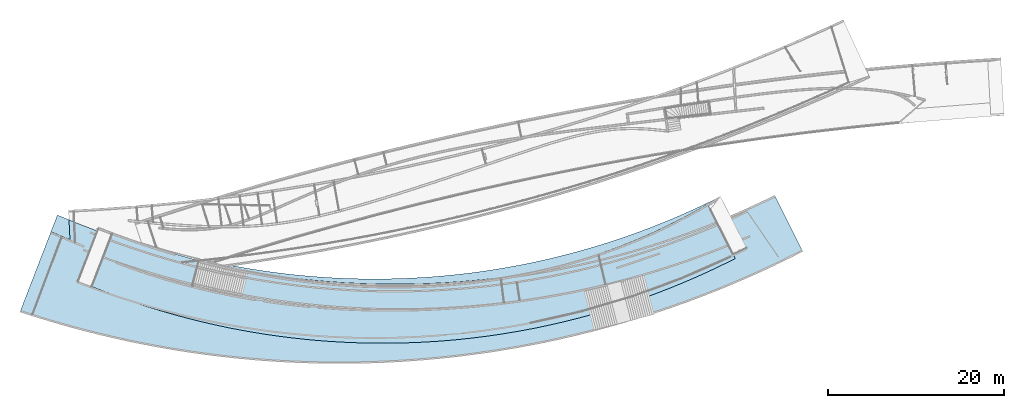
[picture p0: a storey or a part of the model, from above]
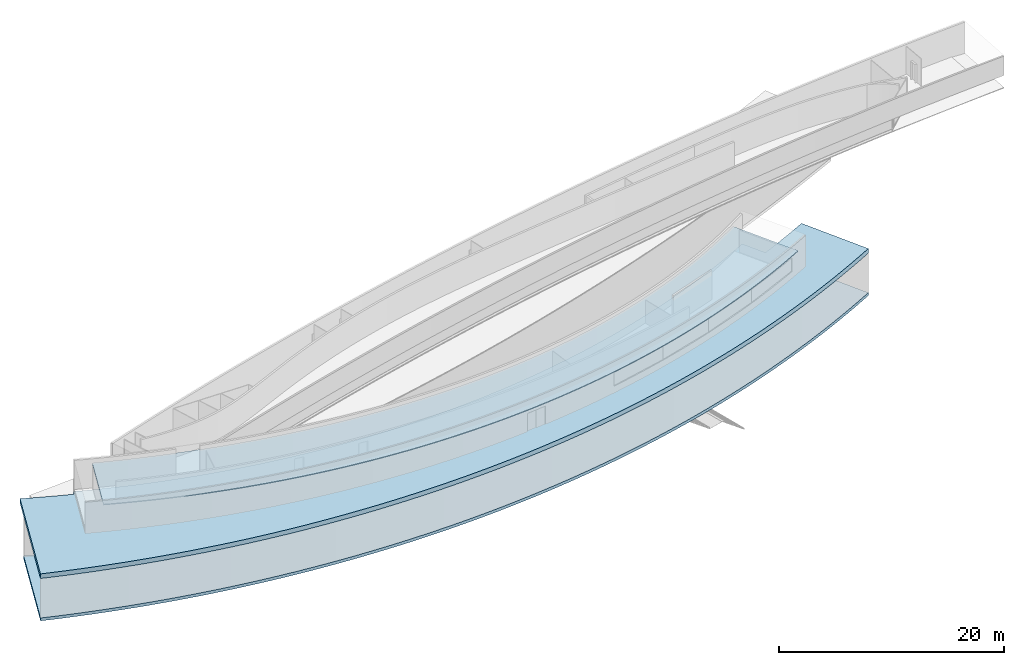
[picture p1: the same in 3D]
Properties of the parts of a building model (IFC2X3)

# File
Description: IFC 2x3 Building Model
Time: 2020-01-24T11:37:14
Made in: ASIFC - 2.14.0.987

# IfcProject
Description: The copyright of this model is belonged to AppliCraft Co., Ltd. The use of this model data is allowed to nonprofit purpose by author's consent . 本モデルの著作権は、株式会社アプリクラフトが所有しています。 本モデルの使用は作者の同意のもとに非営利目的に限り許可されます。

# IfcSite, Site
RefLatitude: 47, 35, 59, 994506; RefLongitude: -122, -17, -59, -983519; RefElevation: 0 mm

# IfcDoor: HOKI (2)
In: Site
Type - OperationType: SINGLE_SWING_LEFT; ParameterTakesPrecedence: yes; Sizeable: no
Type - IfcDoorPanelProperties - PanelDepth: 50 mm; PanelOperation: SWINGING; PanelWidth: 1; PanelPosition: LEFT
Type - IfcDoorLiningProperties - LiningDepth: 100 mm; LiningThickness: 50 mm
OverallHeight: 2000 mm; OverallWidth: 900 mm
IfcElementQuantity - NetVolume: 102000000; NetSideArea: 1800000

# IfcDoor: HOKI entrance
In: Site
Type - OperationType: DOUBLE_DOOR_SLIDING; ParameterTakesPrecedence: yes; Sizeable: no
Type - IfcDoorPanelProperties - PanelDepth: 50 mm; PanelOperation: SLIDING; PanelWidth: 0.5; PanelPosition: LEFT
Type - IfcDoorLiningProperties - LiningDepth: 100 mm; LiningThickness: 50 mm
OverallHeight: 2000 mm; OverallWidth: 2000 mm
IfcElementQuantity - NetSideArea: 4000000; NetVolume: 214750000

# IfcDoor: Hinged (4)
In: Site
Type - OperationType: SINGLE_SWING_LEFT; ParameterTakesPrecedence: yes; Sizeable: no
Type - IfcDoorPanelProperties - PanelDepth: 40 mm; PanelOperation: SWINGING; PanelWidth: 1; PanelPosition: LEFT
Type - IfcDoorLiningProperties - LiningThickness: 50 mm
OverallHeight: 2000 mm; OverallWidth: 700 mm
IfcElementQuantity - NetSideArea: 1400000; NetVolume: 92800000

# IfcDoor: Hinged (001) (7)
In: Site
Type - OperationType: SINGLE_SWING_RIGHT; ParameterTakesPrecedence: yes; Sizeable: no
Type - IfcDoorPanelProperties - PanelDepth: 40 mm; PanelOperation: SWINGING; PanelWidth: 1; PanelPosition: LEFT
Type - IfcDoorLiningProperties - LiningThickness: 50 mm
OverallHeight: 2000 mm; OverallWidth: 700 mm
IfcElementQuantity - NetSideArea: 1400000; NetVolume: 92800000

# IfcDoor: Hinged Double
In: Site
Type - OperationType: DOUBLE_DOOR_SINGLE_SWING; ParameterTakesPrecedence: yes; Sizeable: no
Type - IfcDoorPanelProperties - PanelDepth: 40 mm; PanelOperation: SWINGING; PanelWidth: 0.5; PanelPosition: LEFT
Type - IfcDoorLiningProperties - LiningThickness: 50 mm
OverallHeight: 2000 mm; OverallWidth: 900 mm
IfcElementQuantity - NetSideArea: 1800000; NetVolume: 110400000

# IfcProxy (17)
ProxyType: PRODUCT

# IfcSlab (6)
In: Site
PredefinedType: FLOOR
Name
3 x 
3 x edge

# IfcSlab: HOKI 1FA
In: Site
Type - PredefinedType: FLOOR; Material: Slab layer 1 250 mm
Pset_SlabCommon - LoadBearing: yes
IfcElementQuantity - NominalWidth: 250 mm; NetArea: 599263802; NetVolume: 149815950571

# IfcSlab: HOKI 1FB (2)
In: Site
Type - PredefinedType: FLOOR; Material: Slab layer 1 320 mm
Pset_SlabCommon - LoadBearing: yes
IfcElementQuantity - NominalWidth: 320 mm
Name | NetVolume | NetArea
 | 206045122446 | 643891019
 | 249694791905 | 780296225

# IfcSlab: HOKI 1FB UP
In: Site
Type - PredefinedType: FLOOR; Material: Slab layer 1 500 mm
Pset_SlabCommon - LoadBearing: yes
IfcElementQuantity - NominalWidth: 500 mm; NetVolume: 426551266170; NetArea: 853102532

# IfcSlab: HOKI slab (7)
In: Site
Type - PredefinedType: FLOOR; Material: Slab layer 1 100 mm
Pset_SlabCommon - LoadBearing: yes
IfcElementQuantity - NominalWidth: 100 mm
Name | NetVolume | NetArea
 | 65280736530 | 652807335
 | 46889796477 | 468897965
 | 59784627662 | 597846277
 | 47279152121 | 472791522
 | 44702134236 | 447021343
 | 66015420637 | 660154206
 | 63767994200 | 637679934

# IfcWallStandardCase: HOKI 350 (23)
In: Site
Type - PredefinedType: STANDARD; Material: Wall layer 1 200 mm
Pset_WallCommon - ExtendToStructure: no; LoadBearing: yes
Name | NetVolume | NominalHeight (mm) | NetSideArea | NominalLength (mm)
 | 45368775985 | 3400 | 226843664 | 78422.5
 | 38641224893 | 2100 | 193206422 | 91949
 | 67383342514 | 3400 | 336916713 | 100328
 | 77753672591 | 4280 | 388769785 | 91161.2
 | 65737710868 | 4280 | 328688554 | 76796.4
 | 55125613345 | 4280 | 275704417 | 64416.9
 | 7281568252 | 2950 | 36408594 | 12142.9
 | 12560426585 | 2950 | 62807020 | 21900.7
 | 41611079215 | 2950 | 208075869 | 70534.2
 | 56284857131 | 4500 | 281447824 | 62939.5
 | 65768546809 | 4280 | 328842736 | 76832.4
 | 540286268 | 2950 | 2701440 | 1145.96
 | 1404575006 | 2950 | 6992248 | 2238.25
 | 28552884017 | 2500 | 142770192 | 58548.1
 | 3523440999 | 3400 | 17617205 | 5181.53
 | 41967088291 | 3400 | 209847102 | 61719.7
 | 3800915291 | 4280 | 19004541 | 4734
 | 6288546075 | 3400 | 31442730 | 9247.93
 | 6888132468 | 4280 | 34440819 | 7950.68
 | 2289751343 | 4280 | 11448757 | 2649.92
 | 3534827953 | 4280 | 17674140 | 4129.49
 | 66466808166 | 4280 | 332334042 | 77648.1
 | 78274025843 | 4280 | 391370131 | 91441.7

# IfcWallStandardCase: HOKI 50mm (34)
In: Site
Type - PredefinedType: STANDARD; Material: Wall layer 1 50 mm
Pset_WallCommon - ExtendToStructure: no; LoadBearing: yes
Name | NetSideArea | NetVolume | NominalLength (mm) | NominalHeight (mm)
 | 39514949 | 1975747257 | 9216.39 | 4280
 | 309326638 | 15466328423 | 79107.4 | 3930
 | 8238500 | 411924983 | 2975.33 | 2950
 | 22589403 | 1129470127 | 7647.94 | 2950
 | 1392658 | 69632890 | 633.608 | 2950
 | 4838984 | 241949340 | 1696.43 | 2950
 | 4199716 | 209985976 | 1560.4 | 2950
 | 4928407 | 246420386 | 1834.25 | 2950
 | 9634128 | 513142221 | 3644.23 | 2950
 | 6981735 | 349086735 | 2377.55 | 2950
 | 0 | 2474658 | 659.314 | 2950
 | 6693960 | 334698017 | 2462.66 | 2950
 | 4644896 | 232244784 | 1765.05 | 2950
 | 8261558 | 413077902 | 3460.36 | 2500
 | 6489956 | 324497793 | 2764.03 | 2500
 | 13117511 | 655875261 | 3061.85 | 4280
 | 14273129 | 713656070 | 3333.15 | 4280
 | 14905601 | 745279603 | 3481.41 | 4280
 | 15157558 | 757877459 | 3541.2 | 4280
 | 14657368 | 732868608 | 3426.02 | 4280
 | 13964863 | 698243348 | 3264.76 | 4280
 | 7041466 | 352073376 | 1645.96 | 4280
 | 9249209 | 462460620 | 2315.65 | 4280
 | 7585389 | 379269743 | 2122.74 | 4280
 | 13705763 | 685288241 | 3198.13 | 4280
 | 3296193 | 164809623 | 1116.4 | 2950
 | 2022728 | 101134547 | 5082.05 | 400
 | 2012148 | 100607418 | 5056.13 | 399.999
 | 5750267 | 287513364 | 1298.85 | 4280
 | 15425361 | 771268011 | 3622.12 | 4280
 | 844059 | 42205921 | 1298.87 | 650
 | 1591516 | 79575784 | 6366.25 | 250
 | 14690665 | 734533332 | 3389.62 | 4280
 | 467123 | 23356150 | 1116.4 | 400

# IfcWindow: Fixed (4)
In: Site
Type - OperationType: SINGLE_PANEL; ParameterTakesPrecedence: yes; Sizeable: no
Type - IfcWindowPanelProperties - OperationType: FIXEDCASEMENT; PanelPosition: LEFT; FrameDepth: 50 mm
OverallHeight: 1500 mm; OverallWidth: 6000 mm
IfcElementQuantity - NetSideArea: 9000000; NetVolume: 450000000

# IfcWindow: Style
In: Site
Type - OperationType: SINGLE_PANEL; ParameterTakesPrecedence: no; Sizeable: no
Type - IfcWindowPanelProperties - OperationType: SIDEHUNGLEFTHAND; PanelPosition: LEFT; FrameDepth: 50 mm
OverallHeight: 1050 mm; OverallWidth: 77541 mm
IfcElementQuantity - NetSideArea: 81418062; NetVolume: 0
